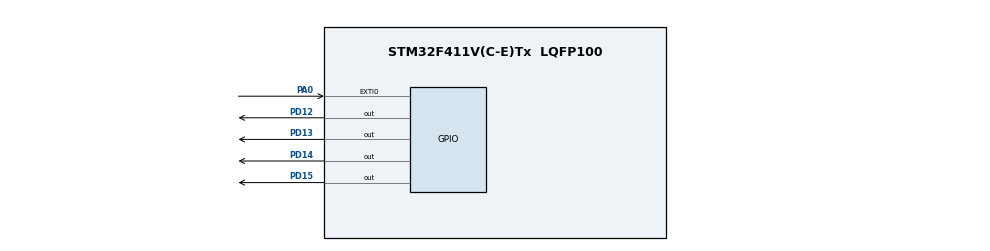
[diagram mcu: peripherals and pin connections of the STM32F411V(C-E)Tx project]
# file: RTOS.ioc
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Mcu.Family=STM32F4
Mcu.Name=STM32F411V(C-E)Tx
Mcu.Package=LQFP100
NVIC.EXTI0_IRQn=true\:6\:0\:true\:false\:true\:true\:true\:true
NVIC.PriorityGroup=NVIC_PRIORITYGROUP_4
NVIC.TIM1_BRK_TIM9_IRQn=true\:15\:0\:false\:false\:true\:false\:true\:true
NVIC.TimeBase=TIM1_BRK_TIM9_IRQn
NVIC.TimeBaseIP=TIM9
PA0-WKUP.GPIO_ModeDefaultEXTI=GPIO_MODE_IT_FALLING
PA0-WKUP.Signal=GPXTI0
PA13.Mode=Serial_Wire
PA13.Signal=SYS_JTMS-SWDIO
PA14.Mode=Serial_Wire
PA14.Signal=SYS_JTCK-SWCLK
PD12.Signal=GPIO_Output
PD13.Signal=GPIO_Output
PD14.Signal=GPIO_Output
PD15.Signal=GPIO_Output
ProjectManager.HeapSize=0x200
ProjectManager.StackSize=0x400
ProjectManager.TargetToolchain=STM32CubeIDE
RCC.AHBFreq_Value=16000000
RCC.APB1Freq_Value=16000000
RCC.APB2Freq_Value=16000000
RCC.CortexFreq_Value=16000000
RCC.HSE_VALUE=25000000
RCC.HSI_VALUE=16000000
RCC.LSE_VALUE=32768
RCC.SYSCLKFreq_VALUE=16000000
RCC.VCOOutputFreq_Value=192000000
VP_SYS_VS_tim9.Mode=TIM9
board=custom

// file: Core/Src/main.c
/* USER CODE BEGIN Header */
/**
  ******************************************************************************
  * @file           : main.c
  * @brief          : Main program body
  ******************************************************************************
  * @attention
  *
  * Copyright (c) 2023 STMicroelectronics.
  * All rights reserved.
  *
  * This software is licensed under terms that can be found in the LICENSE file
  * in the root directory of this software component.
  * If no LICENSE file comes with this software, it is provided AS-IS.
  *
  ******************************************************************************
  */
/* USER CODE END Header */
#include "main.h"

/* USER CODE BEGIN Includes */
#include"stdio.h"
#include"FreeRTOS.h"
#include"task.h"
/* USER CODE END Includes */

/* USER CODE BEGIN PV */
#define DWT_CTRL (*(volatile uint32_t*)0XE0001000)
/* USER CODE END PV */

void SystemClock_Config(void);
static void MX_GPIO_Init(void);
/* USER CODE BEGIN PFP */
static void LEDyellow(void *param);
static void LEDred(void *param);
static void LEDgreen(void *param);
extern void SEGGER_UART_init(U32);
/* USER CODE END PFP */

int main(void)
{
  /* USER CODE BEGIN 1 */
	BaseType_t status;
	TaskHandle_t taskLedGreen,taskLedRed,taskLedYellow;
  /* USER CODE END 1 */

  /* MCU Configuration--------------------------------------------------------*/

  /* Reset of all peripherals, Initializes the Flash interface and the Systick. */
  HAL_Init();

  /* Configure the system clock */
  SystemClock_Config();

  /* Initialize all configured peripherals */
  MX_GPIO_Init();
  /* USER CODE BEGIN 2 */
  DWT_CTRL|=(1<<0);

  SEGGER_UART_init(500000);
  SEGGER_SYSVIEW_Conf();

//  SEGGER_SYSVIEW_Start();

status =xTaskCreate(LEDgreen, "LEDgreen", 100, "LEDgreen", 0, &taskLedGreen);
configASSERT(status==pdPASS);
status =xTaskCreate(LEDred, "LEDred", 100, "LEDred", 2, &taskLedRed);
configASSERT(status==pdPASS);
status=xTaskCreate(LEDyellow, "LEDyellow", 100, "LEDyellow", 2, &taskLedYellow);
configASSERT(status==pdPASS);
vTaskStartScheduler();
  /* USER CODE END 2 */

  /* Infinite loop */
  /* USER CODE BEGIN WHILE */
  while (1)
  {
	  /*
	  HAL_GPIO_TogglePin(GPIOD, GPIO_PIN_15);
	  HAL_GPIO_TogglePin(GPIOD, GPIO_PIN_14);
	  HAL_GPIO_TogglePin(GPIOD, GPIO_PIN_13);
	  HAL_GPIO_TogglePin(GPIOD, GPIO_PIN_12);
	  HAL_Delay(500);
	  */
    /* USER CODE END WHILE */

  }
}

void SystemClock_Config(void)
{
  RCC_OscInitTypeDef RCC_OscInitStruct = {0};
  RCC_ClkInitTypeDef RCC_ClkInitStruct = {0};

  /** Configure the main internal regulator output voltage
  */
  __HAL_RCC_PWR_CLK_ENABLE();
  __HAL_PWR_VOLTAGESCALING_CONFIG(PWR_REGULATOR_VOLTAGE_SCALE1);

  /** Initializes the RCC Oscillators according to the specified parameters
  * in the RCC_OscInitTypeDef structure.
  */
  RCC_OscInitStruct.OscillatorType = RCC_OSCILLATORTYPE_HSI;
  RCC_OscInitStruct.HSIState = RCC_HSI_ON;
  RCC_OscInitStruct.HSICalibrationValue = RCC_HSICALIBRATION_DEFAULT;
  RCC_OscInitStruct.PLL.PLLState = RCC_PLL_ON;
  RCC_OscInitStruct.PLL.PLLSource = RCC_PLLSOURCE_HSI;
  RCC_OscInitStruct.PLL.PLLM = 8;
  RCC_OscInitStruct.PLL.PLLN = 84;
  RCC_OscInitStruct.PLL.PLLP = RCC_PLLP_DIV2;
  RCC_OscInitStruct.PLL.PLLQ = 4;
  if (HAL_RCC_OscConfig(&RCC_OscInitStruct) != HAL_OK)
  {
    Error_Handler();
  }

  /** Initializes the CPU, AHB and APB buses clocks
  */
  RCC_ClkInitStruct.ClockType = RCC_CLOCKTYPE_HCLK|RCC_CLOCKTYPE_SYSCLK
                              |RCC_CLOCKTYPE_PCLK1|RCC_CLOCKTYPE_PCLK2;
  RCC_ClkInitStruct.SYSCLKSource = RCC_SYSCLKSOURCE_PLLCLK;
  RCC_ClkInitStruct.AHBCLKDivider = RCC_SYSCLK_DIV1;
  RCC_ClkInitStruct.APB1CLKDivider = RCC_HCLK_DIV2;
  RCC_ClkInitStruct.APB2CLKDivider = RCC_HCLK_DIV1;

  if (HAL_RCC_ClockConfig(&RCC_ClkInitStruct, FLASH_LATENCY_2) != HAL_OK)
  {
    Error_Handler();
  }
}

static void MX_GPIO_Init(void)
{
  GPIO_InitTypeDef GPIO_InitStruct = {0};

  /* GPIO Ports Clock Enable */
  __HAL_RCC_GPIOD_CLK_ENABLE();

  /*Configure GPIO pin Output Level */
  HAL_GPIO_WritePin(GPIOD, GPIO_PIN_12|GPIO_PIN_13|GPIO_PIN_14|GPIO_PIN_15, GPIO_PIN_RESET);

  /*Configure GPIO pins : PD12 PD13 PD14 PD15 */
  GPIO_InitStruct.Pin = GPIO_PIN_12|GPIO_PIN_13|GPIO_PIN_14|GPIO_PIN_15;
  GPIO_InitStruct.Mode = GPIO_MODE_OUTPUT_PP;
  GPIO_InitStruct.Pull = GPIO_NOPULL;
  GPIO_InitStruct.Speed = GPIO_SPEED_FREQ_LOW;
  HAL_GPIO_Init(GPIOD, &GPIO_InitStruct);

}

/* USER CODE BEGIN 4 */
static void LEDgreen(void *param)
{
	while(1)
	{
		HAL_GPIO_TogglePin(GPIOD, GPIO_PIN_12);
//		printf("%s\n",(char*)param);
		int ticks=pdMS_TO_TICKS(100);
		vTaskDelay(ticks);
	}
}
static void LEDred(void *param)
{
	while(1)
	{
		HAL_GPIO_TogglePin(GPIOD, GPIO_PIN_13);
	//	printf("%s\n",(char*)param);
		vTaskDelay(800);
	}
}
static void LEDyellow(void *param)
{
	while(1)
	{
		HAL_GPIO_TogglePin(GPIOD, GPIO_PIN_14);
		//printf("%s\n",(char*)param);
		vTaskDelay(400);
	}
}
void vApplicationIdleHook(void)
{
	HAL_PWR_EnterSLEEPMode(PWR_MAINREGULATOR_ON, PWR_SLEEPENTRY_WFI);
}
/* USER CODE END 4 */

void HAL_TIM_PeriodElapsedCallback(TIM_HandleTypeDef *htim)
{
  if (htim->Instance == TIM9) {
    HAL_IncTick();
  }
}

void Error_Handler(void)
{
  __disable_irq();
  while (1)
  {
  }
}
